One B-rep face of a CAD part: STEP entity #1210.
In plain terms, the cylindrical face has radius 32.5 mm (diameter 65 mm), a partial arc.
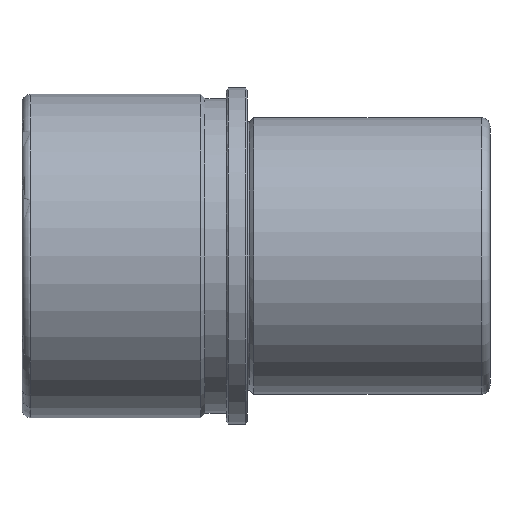
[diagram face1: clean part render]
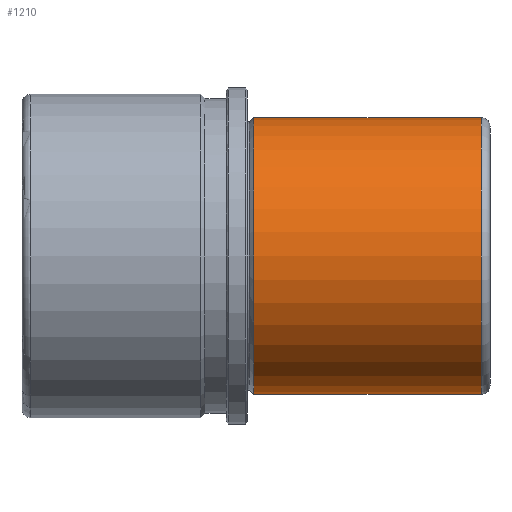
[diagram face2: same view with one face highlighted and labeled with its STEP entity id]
Its self-contained STEP definition (entity closure, numbers rounded to 3 decimals):
#968=CARTESIAN_POINT('Vertex',(55.,0.,32.5)) ;
#975=CARTESIAN_POINT('Vertex',(55.,0.,-32.5)) ;
#1004=CARTESIAN_POINT('Axis2P3D Location',(55.,0.,0.)) ;
#1008=CARTESIAN_POINT('Vertex',(55.,-32.5,0.)) ;
#1011=CARTESIAN_POINT('Axis2P3D Location',(55.,0.,0.)) ;
#1150=CARTESIAN_POINT('Line Origine',(57.,0.,32.5)) ;
#1154=CARTESIAN_POINT('Vertex',(1.414,0.,32.5)) ;
#1157=CARTESIAN_POINT('Line Origine',(57.,0.,-32.5)) ;
#1161=CARTESIAN_POINT('Vertex',(1.414,0.,-32.5)) ;
#1185=CARTESIAN_POINT('Axis2P3D Location',(57.,0.,0.)) ;
#1190=CARTESIAN_POINT('Axis2P3D Location',(1.414,0.,0.)) ;
#1194=CARTESIAN_POINT('Vertex',(1.414,-32.5,0.)) ;
#1197=CARTESIAN_POINT('Axis2P3D Location',(1.414,0.,0.)) ;
#1005=DIRECTION('Axis2P3D Direction',(1.,0.,-0.)) ;
#1012=DIRECTION('Axis2P3D Direction',(1.,0.,-0.)) ;
#1151=DIRECTION('Vector Direction',(-1.,0.,0.)) ;
#1158=DIRECTION('Vector Direction',(-1.,0.,0.)) ;
#1186=DIRECTION('Axis2P3D Direction',(-1.,-0.,-0.)) ;
#1187=DIRECTION('Axis2P3D XDirection',(0.,0.,-1.)) ;
#1191=DIRECTION('Axis2P3D Direction',(-1.,-0.,-0.)) ;
#1198=DIRECTION('Axis2P3D Direction',(-1.,-0.,-0.)) ;
#1006=AXIS2_PLACEMENT_3D('Circle Axis2P3D',#1004,#1005,$) ;
#1013=AXIS2_PLACEMENT_3D('Circle Axis2P3D',#1011,#1012,$) ;
#1188=AXIS2_PLACEMENT_3D('Cylinder Axis2P3D',#1185,#1186,#1187) ;
#1192=AXIS2_PLACEMENT_3D('Circle Axis2P3D',#1190,#1191,$) ;
#1199=AXIS2_PLACEMENT_3D('Circle Axis2P3D',#1197,#1198,$) ;
#1203=ORIENTED_EDGE('',*,*,#1163,.T.) ;
#1204=ORIENTED_EDGE('',*,*,#1015,.F.) ;
#1205=ORIENTED_EDGE('',*,*,#1010,.F.) ;
#1206=ORIENTED_EDGE('',*,*,#1156,.T.) ;
#1207=ORIENTED_EDGE('',*,*,#1196,.T.) ;
#1208=ORIENTED_EDGE('',*,*,#1201,.T.) ;
#1152=VECTOR('Line Direction',#1151,1.) ;
#1159=VECTOR('Line Direction',#1158,1.) ;
#1210=ADVANCED_FACE('FAMO-SF1-D52 x 110',(#1209),#1189,.T.) ;
#1007=CIRCLE('generated circle',#1006,32.5) ;
#1014=CIRCLE('generated circle',#1013,32.5) ;
#1193=CIRCLE('generated circle',#1192,32.5) ;
#1200=CIRCLE('generated circle',#1199,32.5) ;
#1189=CYLINDRICAL_SURFACE('generated cylinder',#1188,32.5) ;
#1010=EDGE_CURVE('',#969,#1009,#1007,.T.) ;
#1015=EDGE_CURVE('',#1009,#976,#1014,.T.) ;
#1156=EDGE_CURVE('',#969,#1155,#1153,.T.) ;
#1163=EDGE_CURVE('',#1162,#976,#1160,.F.) ;
#1196=EDGE_CURVE('',#1155,#1195,#1193,.F.) ;
#1201=EDGE_CURVE('',#1195,#1162,#1200,.F.) ;
#1202=EDGE_LOOP('',(#1203,#1204,#1205,#1206,#1207,#1208)) ;
#1209=FACE_OUTER_BOUND('',#1202,.T.) ;
#1153=LINE('Line',#1150,#1152) ;
#1160=LINE('Line',#1157,#1159) ;
#969=VERTEX_POINT('',#968) ;
#976=VERTEX_POINT('',#975) ;
#1009=VERTEX_POINT('',#1008) ;
#1155=VERTEX_POINT('',#1154) ;
#1162=VERTEX_POINT('',#1161) ;
#1195=VERTEX_POINT('',#1194) ;
